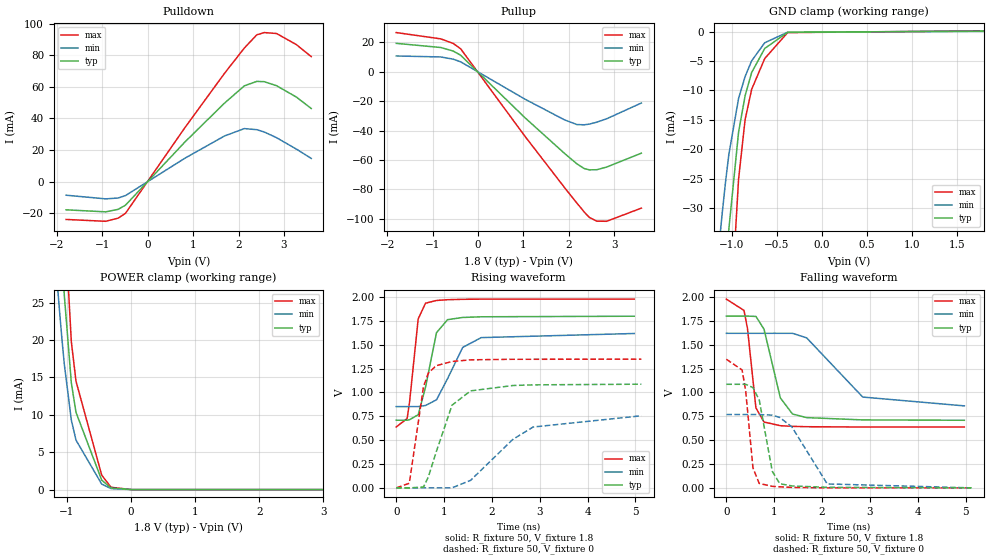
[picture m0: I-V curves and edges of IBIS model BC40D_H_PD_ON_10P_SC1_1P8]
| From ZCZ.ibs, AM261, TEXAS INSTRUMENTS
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[Model]   BC40D_H_PD_ON_10P_SC1_1P8
Model_type   I/O
Polarity   Non-Inverting
Enable   Active-Low
Vinl =  0.63
Vinh =  1.17
Cref =  15pF
Rref =  100.0000M
Vref =  0V
Vmeas =  0.9
C_comp   2.389419p   2.292106p   2.408415p
|[Input load] weak_pd_on
|[Output drive] slow
|[supplytol] 10
|[temp] ind
[Model Spec]
Vinl   0.63   0.567   0.693
Vinh   1.17   1.053   1.287
[Temperature Range]   25   125   -40
[Voltage Range]   1.8   1.62   1.98
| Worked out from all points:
|   slope of the pulldown table from 0 to 0.27 V, typ, clamps not added: 32.2 ohm
|   slope of the pullup table from 0 to 0.27 V, typ, clamps not added: 32.6 ohm
|   GND clamp passes 1 mA (typ) near -0.53 V on its own axis
|   POWER clamp passes 1 mA (typ) near -0.43 V on its own axis
|   rising waveform, R_fixture 50, V_fixture 1.8: 20-80 % time 249ps typ, 424ps min, 162ps max; typ from 0.709 V to 1.8 V
|   rising waveform, R_fixture 50, V_fixture 0: 20-80 % time 429ps typ, 994ps min, 231ps max; typ from 0 V to 1.09 V
|   falling waveform, R_fixture 50, V_fixture 1.8: 20-80 % time 310ps typ, 792ps min, 166ps max; typ from 1.8 V to 0.708 V
|   falling waveform, R_fixture 50, V_fixture 0: 20-80 % time 227ps typ, 467ps min, 151ps max; typ from 1.08 V to 0 V
| Nom Voltages:
|   VDD=1.1001, VDDS=1.8, VDDS18=1.8, ESD_BIASFET=0, VSS=0, VSSS=0
| Min Voltages:
|   VDD=0.99, VDDS=1.62, VDDS18=1.62, ESD_BIASFET=0, VSS=0, VSSS=0
| Max Voltages:
|   VDD=1.21, VDDS=1.98, VDDS18=1.98, ESD_BIASFET=0, VSS=0, VSSS=0
[POWER_clamp]
|   voltage   I(typ)   I(min)   I(max)
-1.8V     158.9mA    112.6mA    219.9mA
-1.255V   60.04mA    40.04mA    85.04mA
-1.145V   41.99mA    27.45mA    59.9mA
-1.109V   36.4mA     23.66mA    51.96mA
-1.073V   31.04mA    20.08mA    44.3mA
-1.036V   25.91mA    16.71mA    36.9mA
-927.3mV  14.27mA    9.297mA    19.77mA
-854.5mV  10.33mA    6.619mA    14.49mA
-454.5mV  1.273mA    741.7uA    1.94mA
-309.1mV  221.6uA    132.8uA    307.8uA
18.18mV   0A         0A         0A
3.6V      0A         0A         0A
[Pulldown]
|   voltage   I(typ)   I(min)   I(max)
-1.8V     -17.92mA   -8.674mA   -24.03mA
-927.3mV  -19.22mA   -10.99mA   -25.2mA
-654.5mV  -17.65mA   -10.46mA   -23.22mA
-490.9mV  -14.97mA   -8.904mA   -20.12mA
818.2mV   25.05mA    14.78mA    34.16mA
1.691V    49.7mA     28.87mA    68.58mA
2.127V    60.63mA    33.53mA    84.59mA
2.4V      63.43mA    32.84mA    92.9mA
2.564V    63.25mA    31.38mA    94.36mA
2.836V    60.69mA    27.76mA    93.76mA
3.273V    53.49mA    20.53mA    86.73mA
3.6V      46.26mA    14.64mA    79.12mA
[Pullup]
|   voltage   I(typ)   I(min)   I(max)
-1.8V     19.42mA    10.82mA    26.76mA
-818.2mV  16.58mA    10.15mA    22.47mA
-545.5mV  14.19mA    8.648mA    19.37mA
-381.8mV  11.34mA    6.842mA    15.75mA
1.036V    -31.26mA   -18.6mA    -43.9mA
1.909V    -55.59mA   -32.73mA   -78.89mA
2.182V    -62.71mA   -35.92mA   -89.46mA
2.345V    -65.94mA   -36.05mA   -95.62mA
2.455V    -66.75mA   -35.58mA   -99.18mA
2.618V    -66.67mA   -34.29mA   -101.7mA
2.836V    -64.86mA   -31.95mA   -101.8mA
3.6V      -55.4mA    -21.22mA   -92.82mA
[GND_clamp]
|   voltage   I(typ)   I(min)   I(max)
-1.8V     -270.2mA   -170.2mA   -430.1mA
-1.255V   -91.66mA   -55.91mA   -148.4mA
-1.145V   -59.91mA   -36.45mA   -97.1mA
-1.109V   -50.48mA   -30.83mA   -81.56mA
-1.073V   -41.73mA   -25.65mA   -67.06mA
-1.036V   -33.67mA   -20.93mA   -53.6mA
-927.3mV  -17.08mA   -11.35mA   -25.06mA
-854.5mV  -10.88mA   -7.623mA   -14.95mA
-781.8mV  -6.944mA   -4.955mA   -9.81mA
-636.4mV  -2.852mA   -1.883mA   -4.568mA
-381.8mV  -107.5uA   -91.83uA   -158.4uA
1.8V      101.9uA    59.86uA    152.6uA
[Ramp]
| variable   typ   min   max
dV/dt_f  0.6608501/0.31247664n 0.46735341/0.81405775n 0.80986843/0.1677152n
dV/dt_r 0.65873657/0.43263011n 0.47402485/1.0517225n 0.81471545/0.23230577n
R_load = 50
[Rising Waveform]
R_fixture = 50
V_fixture = 1.8
V_fixture_min = 1.62
V_fixture_max = 1.98
|   time   V(typ)   V(min)   V(max)
0s        708.5mV    851.3mV    637.8mV
228.1ps   708.5mV    851.3mV    726mV
278.6ps   714.1mV    851.3mV    895.7mV
459.6ps   765.9mV    851.6mV    1.77V
612.3ps   1.054V     862.9mV    1.934V
841.8ps   1.626V     922.1mV    1.963V
1.074ns   1.762V     1.145V     1.971V
1.389ns   1.785V     1.471V     1.975V
1.777ns   1.792V     1.574V     1.977V
4.974ns   1.798V     1.617V     1.977V
[Rising Waveform]
R_fixture = 50
V_fixture = 0
V_fixture_min = 0
V_fixture_max = 0
|   time   V(typ)   V(min)   V(max)
0s        0V         0V         0V
273.6ps   0V         0V         47.5mV
570.6ps   8.425mV    0V         1.06V
671ps     114mV      0V         1.202V
834.9ps   374.1mV    0V         1.28V
1.166ns   866mV      0V         1.324V
1.554ns   1.016V     78.57mV    1.341V
2.437ns   1.072V     507.4mV    1.347V
2.86ns    1.079V     637.3mV    1.347V
5.123ns   1.086V     754.9mV    1.348V
[Falling Waveform]
R_fixture = 50
V_fixture = 1.8
V_fixture_min = 1.62
V_fixture_max = 1.98
|   time   V(typ)   V(min)   V(max)
0s        1.799V     1.619V     1.977V
369ps     1.799V     1.619V     1.859V
442.1ps   1.799V     1.619V     1.669V
618.1ps   1.796V     1.619V     837.9mV
787.7ps   1.662V     1.619V     689.6mV
1.129ns   942.3mV    1.619V     651.2mV
1.383ns   773.4mV    1.619V     644.4mV
1.679ns   735.8mV    1.571V     640.5mV
2.85ns    711.8mV    951.1mV    637.2mV
4.974ns   708.1mV    858.7mV    637mV
[Falling Waveform]
R_fixture = 50
V_fixture = 0
V_fixture_min = 0
V_fixture_max = 0
|   time   V(typ)   V(min)   V(max)
0s        1.085V     768mV      1.347V
329.5ps   1.085V     768mV      1.235V
404.9ps   1.085V     768mV      1.014V
556.5ps   1.05V      768mV      209.1mV
687.9ps   920.5mV    768mV      45.88mV
960ps     173.5mV    761.9mV    15.98mV
1.117ns   43.4mV     737.3mV    11.07mV
1.37ns    20.14mV    638.2mV    4.644mV
2.109ns   5.655mV    41.02mV    0V
5.123ns   0V         0V         0V
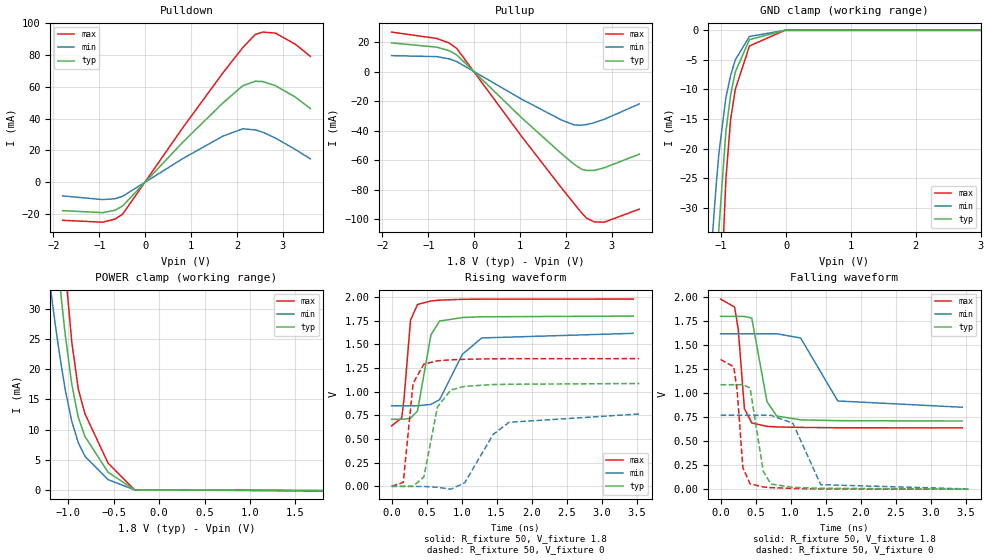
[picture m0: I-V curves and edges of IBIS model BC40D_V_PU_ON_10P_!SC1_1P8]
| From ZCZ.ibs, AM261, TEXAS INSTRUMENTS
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[Model]   BC40D_V_PU_ON_10P_!SC1_1P8
Model_type   I/O
Polarity   Non-Inverting
Enable   Active-Low
Vinl =  0.63
Vinh =  1.17
Cref =  15pF
Rref =  100.0000M
Vref =  0V
Vmeas =  0.9
C_comp   2.290246p   2.205796p   2.292736p
|[Input load] weak_pu_on
|[Output drive] fast
|[supplytol] 10
|[temp] ind
[Model Spec]
Vinl   0.63   0.567   0.693
Vinh   1.17   1.053   1.287
[Temperature Range]   25   125   -40
[Voltage Range]   1.8   1.62   1.98
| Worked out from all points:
|   slope of the pulldown table from 0 to 0.27 V, typ, clamps not added: 32.2 ohm
|   slope of the pullup table from 0 to 0.27 V, typ, clamps not added: 32.5 ohm
|   GND clamp passes 1 mA (typ) near -0.52 V on its own axis
|   POWER clamp passes 1 mA (typ) near -0.44 V on its own axis
|   rising waveform, R_fixture 50, V_fixture 1.8: 20-80 % time 141ps typ, 321ps min, 87.2ps max; typ from 0.71 V to 1.8 V
|   rising waveform, R_fixture 50, V_fixture 0: 20-80 % time 174ps typ, 380ps min, 98.7ps max; typ from 0.003 V to 1.09 V
|   falling waveform, R_fixture 50, V_fixture 1.8: 20-80 % time 128ps typ, 290ps min, 84ps max; typ from 1.8 V to 0.711 V
|   falling waveform, R_fixture 50, V_fixture 0: 20-80 % time 111ps typ, 211ps min, 81ps max; typ from 1.09 V to 0.002 V
| Nom Voltages:
|   VDD=1.1001, VDDS=1.8, VDDS18=1.8, ESD_BIASFET=0, VSS=0, VSSS=0
| Min Voltages:
|   VDD=0.99, VDDS=1.62, VDDS18=1.62, ESD_BIASFET=0, VSS=0, VSSS=0
| Max Voltages:
|   VDD=1.21, VDDS=1.98, VDDS18=1.98, ESD_BIASFET=0, VSS=0, VSSS=0
[POWER_clamp]
|   voltage   I(typ)   I(min)   I(max)
-1.8V     158.8mA    112.5mA    219.8mA
-1.255V   59.97mA    40.01mA    84.9mA
-1.145V   41.92mA    27.42mA    59.75mA
-1.109V   36.32mA    23.63mA    51.82mA
-1.073V   30.96mA    20.05mA    44.15mA
-1.036V   25.83mA    16.67mA    36.75mA
-963.6mV  17.54mA    11.39mA    24.55mA
-890.9mV  12.01mA    7.801mA    16.66mA
-818.2mV  8.875mA    5.6mA      12.63mA
-563.6mV  2.954mA    1.727mA    4.458mA
-272.7mV  55.97uA    39.41uA    57.82uA
1.8V      -99.94uA   -59.68uA   -146.8uA
[Pulldown]
|   voltage   I(typ)   I(min)   I(max)
-1.8V     -17.92mA   -8.674mA   -24.03mA
-927.3mV  -19.22mA   -10.99mA   -25.21mA
-654.5mV  -17.65mA   -10.46mA   -23.22mA
-490.9mV  -14.97mA   -8.904mA   -20.12mA
818.2mV   25.06mA    14.78mA    34.16mA
1.691V    49.7mA     28.87mA    68.59mA
2.127V    60.63mA    33.53mA    84.59mA
2.4V      63.43mA    32.84mA    92.9mA
2.564V    63.25mA    31.38mA    94.36mA
2.836V    60.69mA    27.76mA    93.76mA
3.273V    53.49mA    20.53mA    86.73mA
3.6V      46.26mA    14.64mA    79.11mA
[Pullup]
|   voltage   I(typ)   I(min)   I(max)
-1.8V     19.47mA    10.86mA    26.81mA
-818.2mV  16.61mA    10.18mA    22.5mA
-545.5mV  14.21mA    8.665mA    19.39mA
-381.8mV  11.35mA    6.855mA    15.77mA
1.036V    -31.31mA   -18.66mA   -43.94mA
1.909V    -55.72mA   -32.86mA   -78.99mA
2.182V    -62.87mA   -36.1mA    -89.59mA
2.345V    -66.12mA   -36.26mA   -95.76mA
2.455V    -66.95mA   -35.82mA   -99.33mA
2.618V    -66.9mA    -34.58mA   -101.8mA
2.836V    -65.13mA   -32.3mA    -102mA
3.6V      -55.92mA   -21.86mA   -93.15mA
[GND_clamp]
|   voltage   I(typ)   I(min)   I(max)
-1.8V     -270.2mA   -170.2mA   -430.1mA
-1.255V   -91.68mA   -55.92mA   -148.5mA
-1.145V   -59.94mA   -36.46mA   -97.15mA
-1.109V   -50.51mA   -30.84mA   -81.62mA
-1.073V   -41.77mA   -25.67mA   -67.14mA
-1.036V   -33.71mA   -20.94mA   -53.69mA
-927.3mV  -17.15mA   -11.38mA   -25.2mA
-854.5mV  -10.96mA   -7.657mA   -15.09mA
-781.8mV  -7.031mA   -4.995mA   -9.958mA
-563.6mV  -1.569mA   -1.036mA   -2.651mA
-18.18mV  0A         0A         0A
3.6V      0A         0A         0A
[Ramp]
| variable   typ   min   max
dV/dt_f  0.6650793/0.13041675n 0.47054236/0.29704481n 0.81398134/85.756989p
dV/dt_r 0.66369803/0.17655946n 0.48061665/0.39565974n 0.81803201/99.446129p
R_load = 50
[Rising Waveform]
R_fixture = 50
V_fixture = 1.8
V_fixture_min = 1.62
V_fixture_max = 1.98
|   time   V(typ)   V(min)   V(max)
0s        710.4mV    852.8mV    640.4mV
144.3ps   710.4mV    852.8mV    725.7mV
175.6ps   710.4mV    852.8mV    911.9mV
270.1ps   722mV      852.8mV    1.757V
370ps     797.4mV    852.8mV    1.923V
562.2ps   1.602V     867mV      1.96V
684.5ps   1.747V     917.1mV    1.969V
1.012ns   1.785V     1.397V     1.977V
1.288ns   1.793V     1.569V     1.979V
3.453ns   1.8V       1.618V     1.98V
[Rising Waveform]
R_fixture = 50
V_fixture = 0
V_fixture_min = 0
V_fixture_max = 0
|   time   V(typ)   V(min)   V(max)
0s        2.784mV    0V         2.119mV
166.4ps   2.784mV    0V         43.04mV
306.9ps   2.784mV    0V         1.091V
461ps     100.5mV    0V         1.292V
655.4ps   840.3mV    -8.842mV   1.328V
846.9ps   1.02V      -28.35mV   1.338V
1.045ns   1.058V     39.43mV    1.344V
1.45ns    1.077V     549.2mV    1.349V
1.678ns   1.08V      678mV      1.35V
3.539ns   1.088V     766.3mV    1.351V
[Falling Waveform]
R_fixture = 50
V_fixture = 1.8
V_fixture_min = 1.62
V_fixture_max = 1.98
|   time   V(typ)   V(min)   V(max)
0s        1.8V       1.619V     1.98V
200.7ps   1.8V       1.619V     1.897V
252.9ps   1.8V       1.619V     1.661V
340.6ps   1.8V       1.619V     841.1mV
445.7ps   1.782V     1.619V     691.1mV
662.6ps   914.6mV    1.619V     655.8mV
801.7ps   763.7mV    1.619V     649.7mV
1.144ns   723.8mV    1.575V     644.9mV
1.675ns   715.2mV    919.9mV    641.1mV
3.453ns   711.4mV    854.9mV    639.8mV
[Falling Waveform]
R_fixture = 50
V_fixture = 0
V_fixture_min = 0
V_fixture_max = 0
|   time   V(typ)   V(min)   V(max)
0s        1.089V     771mV      1.351V
188.4ps   1.089V     771mV      1.276V
237.3ps   1.089V     771mV      1.026V
319ps     1.089V     771mV      224.9mV
421.8ps   1.054V     771mV      57.69mV
608.8ps   191.6mV    771mV      25.46mV
717.5ps   56.12mV    771mV      18.73mV
1.033ns   20.81mV    688.6mV    9.86mV
1.431ns   11.84mV    49.28mV    4.351mV
3.539ns   2.48mV     4.818mV    2.572mV
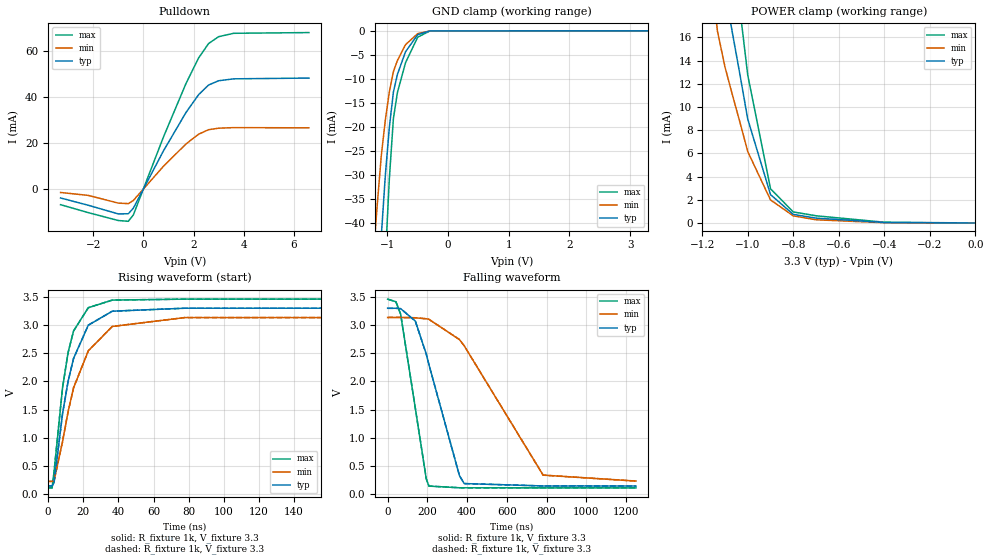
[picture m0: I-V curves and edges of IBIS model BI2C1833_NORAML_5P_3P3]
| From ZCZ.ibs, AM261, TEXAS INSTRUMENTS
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[Model]   BI2C1833_NORAML_5P_3P3
Model_type   I/O_open_drain
Polarity   Non-Inverting
Enable   Active-Low
Vinl =  0.99
Vinh =  2.31
Cref =  400pF
Rref =  528
Vref =  1.8V
Vmeas =  1.65
C_comp   3.826936p   3.027817p   5.265318p
|[Input load] normal
|[Output drive] i2c standard
|[supplytol] 5
|[temp] ind
[Model Spec]
Vinl   0.99   0.9405   1.0395
Vinh   2.31   2.1945   2.4255
[Temperature Range]   25   125   -40
[Voltage Range]   3.3   3.135   3.465
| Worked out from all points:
|   slope of the pulldown table from 0 to 0.495 V, typ, clamps not added: 47.7 ohm
|   GND clamp passes 1 mA (typ) near -0.51 V on its own axis
|   POWER clamp passes 1 mA (typ) near -0.81 V on its own axis
|   rising waveform, R_fixture 1k, V_fixture 3.3: 20-80 % time 11.5ns typ, 15.6ns min, 8.94ns max; typ from 0.147 V to 3.29 V
|   rising waveform, R_fixture 1k, V_fixture 3.3: 20-80 % time 11.5ns typ, 15.6ns min, 8.94ns max; typ from 0.147 V to 3.29 V
|   falling waveform, R_fixture 1k, V_fixture 3.3: 20-80 % time 149ns typ, 298ns min, 87.8ns max; typ from 3.29 V to 0.148 V
|   falling waveform, R_fixture 1k, V_fixture 3.3: 20-80 % time 149ns typ, 298ns min, 87.8ns max; typ from 3.29 V to 0.148 V
| Nom Voltages:
|   VDD=1.1, VDDS=3.3, VDDS18=1.8, ESD_BIASFET=0, VSS=0, VSSS=0
| Min Voltages:
|   VDD=1.045, VDDS=3.135, VDDS18=1.71, ESD_BIASFET=0, VSS=0, VSSS=0
| Max Voltages:
|   VDD=1.16, VDDS=3.465, VDDS18=1.89, ESD_BIASFET=0, VSS=0, VSSS=0
[POWER_clamp]
|   voltage   I(typ)   I(min)   I(max)
-3.3V     371.9mA    388.4mA    506.1mA
-1.133V   24.49mA    16.54mA    35.36mA
-1.1V     20.05mA    13.45mA    29.07mA
-1.067V   16.35mA    11.02mA    23.63mA
-1.033V   12.65mA    8.59mA     18.19mA
-1V       8.957mA    6.159mA    12.75mA
-900mV    2.454mA    1.996mA    2.955mA
-800mV    749.9uA    621.7uA    960.1uA
-700mV    426.8uA    284.2uA    628.2uA
-400mV    48.77uA    29.42uA    72.75uA
0V        4.596uA    2.363uA    8.162uA
[Pulldown]
|   voltage   I(typ)   I(min)   I(max)
-3.3V     -3.962mA   -1.566mA   -6.892mA
-2.2V     -7.129mA   -2.83mA    -10.34mA
-1V       -10.91mA   -6.197mA   -13.79mA
-600mV    -10.84mA   -6.43mA    -14.13mA
-400mV    -8.438mA   -5.051mA   -11.37mA
800mV     16.55mA    9.845mA    22.58mA
1.7V      33.31mA    19.59mA    45.95mA
2.2V      41.03mA    23.82mA    57.03mA
2.6V      45.28mA    25.8mA     63.35mA
3V        47.13mA    26.45mA    66.34mA
3.6V      47.96mA    26.7mA     67.81mA
6.6V      48.3mA     26.61mA    68.13mA
[GND_clamp]
|   voltage   I(typ)   I(min)   I(max)
-3.3V     -732.9mA   -599.4mA   -1.135A
-1.233V   -77.75mA   -47.44mA   -124.9mA
-1.167V   -59.87mA   -36.39mA   -96.3mA
-1.1V     -42.93mA   -26.1mA    -68.88mA
-1.033V   -30.16mA   -18.6mA    -47.71mA
-966.7mV  -20.1mA    -12.73mA   -30.83mA
-900mV    -12.77mA   -8.485mA   -18.26mA
-833.3mV  -9.047mA   -6.155mA   -12.83mA
-700mV    -4.35mA    -2.883mA   -6.626mA
-500mV    -792.1uA   -573.2uA   -1.328mA
-300mV    -20.03uA   -28.2uA    -28.24uA
3.3V      4.596uA    3.242uA    6.322uA
[Ramp]
| variable   typ   min   max
dV/dt_f  1.8954882/0.14919739u  1.7458939/0.29989013u  2.0144794/88.244267n
dV/dt_r 85.098381m/13.233785n 76.442562m/6.1757671n  84.12638m/9.4373148n
R_load = 1k
[Rising Waveform]
R_fixture = 1k
V_fixture = 3.3
V_fixture_min = 3.135
V_fixture_max = 3.465
|   time   V(typ)   V(min)   V(max)
0s        147.5mV    229mV      115mV
2.251ns   147.5mV    229mV      113.9mV
3.336ns   202.4mV    234.2mV    389.5mV
8.186ns   1.428V     933.6mV    1.888V
11.34ns   2V         1.461V     2.511V
14.48ns   2.409V     1.888V     2.895V
22.85ns   2.997V     2.542V     3.306V
36.5ns    3.244V     2.974V     3.441V
77.75ns   3.297V     3.131V     3.458V
1.25us    3.295V     3.133V     3.457V
[Rising Waveform]
R_fixture = 1k
V_fixture = 3.3
V_fixture_min = 3.135
V_fixture_max = 3.465
|   time   V(typ)   V(min)   V(max)
0s        147.5mV    229mV      115mV
2.251ns   147.5mV    229mV      113.9mV
3.336ns   202.4mV    234.2mV    389.5mV
8.186ns   1.428V     933.6mV    1.888V
11.34ns   2V         1.461V     2.511V
14.48ns   2.409V     1.888V     2.895V
22.85ns   2.997V     2.542V     3.306V
36.5ns    3.244V     2.974V     3.441V
77.75ns   3.297V     3.131V     3.458V
1.25us    3.295V     3.133V     3.457V
[Falling Waveform]
R_fixture = 1k
V_fixture = 3.3
V_fixture_min = 3.135
V_fixture_max = 3.465
|   time   V(typ)   V(min)   V(max)
0s        3.295V     3.132V     3.457V
41.91ns   3.295V     3.132V     3.41V
65.72ns   3.288V     3.132V     3.189V
139.5ns   3.068V     3.127V     1.525V
194.6ns   2.484V     3.109V     274.5mV
207.8ns   2.3V       3.1V       147.6mV
361.5ns   332.5mV    2.742V     117.7mV
385.2ns   191.9mV    2.633V     117.4mV
782.6ns   149.9mV    341.4mV    116.1mV
1.25us    148.5mV    236.1mV    116mV
[Falling Waveform]
R_fixture = 1k
V_fixture = 3.3
V_fixture_min = 3.135
V_fixture_max = 3.465
|   time   V(typ)   V(min)   V(max)
0s        3.295V     3.132V     3.457V
41.91ns   3.295V     3.132V     3.41V
65.72ns   3.288V     3.132V     3.189V
139.5ns   3.068V     3.127V     1.525V
194.6ns   2.484V     3.109V     274.5mV
207.8ns   2.3V       3.1V       147.6mV
361.5ns   332.5mV    2.742V     117.7mV
385.2ns   191.9mV    2.633V     117.4mV
782.6ns   149.9mV    341.4mV    116.1mV
1.25us    148.5mV    236.1mV    116mV
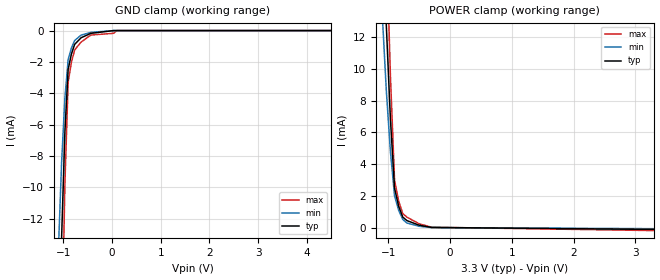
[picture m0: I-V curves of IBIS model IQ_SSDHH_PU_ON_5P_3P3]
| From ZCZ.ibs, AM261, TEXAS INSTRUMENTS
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[Model]   IQ_SSDHH_PU_ON_5P_3P3
Model_type   Input
Polarity   Non-Inverting
Vinl =  0.8V
Vinh =  2V
C_comp   1.115166p   0.9969108p   1.462567p
|[Input load] weak_pu_on
|[supplytol] 5
|[temp] ind
[Model Spec]
Vinl   0.8V   0.8V   0.8V
Vinh   2V   2V   2V
[Temperature Range]   25   125   -40
[Voltage Range]   3.3   3.135   3.465
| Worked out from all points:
|   GND clamp passes 1 mA (typ) near -0.78 V on its own axis
|   POWER clamp passes 1 mA (typ) near -0.80 V on its own axis
| Nom Voltages:
|   VDD=1.1, VDDS=3.3, VDDS18=1.8, BUS_VSSS=0, ESD_BIASFET=0, VSS=0
| Min Voltages:
|   VDD=1.045, VDDS=3.135, VDDS18=1.71, BUS_VSSS=0, ESD_BIASFET=0, VSS=0
| Max Voltages:
|   VDD=1.16, VDDS=3.465, VDDS18=1.89, BUS_VSSS=0, ESD_BIASFET=0, VSS=0
[POWER_clamp]
|   voltage   I(typ)   I(min)   I(max)
-3.3V     372.1mA    388.5mA    506.4mA
-1.1V     20.1mA     13.48mA    29.14mA
-1.033V   12.7mA     8.617mA    18.25mA
-966.7mV  6.831mA    4.797mA    9.545mA
-900mV    2.493mA    2.019mA    3.013mA
-833.3mV  1.354mA    1.101mA    1.678mA
-766.7mV  674.6uA    528.5uA    898.2uA
-700mV    455.9uA    301.6uA    672.6uA
-500mV    162.9uA    94.87uA    253.4uA
-300mV    23.19uA    14.14uA    37.02uA
3.3V      -100.3uA   -54.44uA   -173uA
[GND_clamp]
|   voltage   I(typ)   I(min)   I(max)
-3.3V     -586.5mA   -522.8mA   -870.8mA
-1.1V     -22.37mA   -13.97mA   -35.2mA
-1.033V   -13.09mA   -8.34mA    -20.44mA
-966.7mV  -6.465mA   -4.3mA     -9.807mA
-900mV    -2.481mA   -1.85mA    -3.307mA
-833.3mV  -1.501mA   -1.117mA   -2.022mA
-766.7mV  -878uA     -631.5uA   -1.238mA
-633.3mV  -455.6uA   -289.1uA   -727.4uA
-433.3mV  -176.8uA   -114.8uA   -285.2uA
33.33mV   0A         0A         -174uA
100mV     0A         0A         0A
6.6V      0A         0A         0A
